VERSION 5.8 ;
BUSBITCHARS "[]" ;
DIVIDERCHAR "/" ;
UNITS
    DATABASE MICRONS 2000 ;
END UNITS

VIA softmax_rowwise_int8_r4_wrapper_via1_2_960_340_1_3_300_300
  VIARULE Via1Array-0 ;
  CUTSIZE 0.07 0.07 ;
  LAYERS metal1 via1 metal2 ;
  CUTSPACING 0.08 0.08 ;
  ENCLOSURE 0.035 0.05 0.035 0.035 ;
  ROWCOL 1 3 ;
END softmax_rowwise_int8_r4_wrapper_via1_2_960_340_1_3_300_300

VIA softmax_rowwise_int8_r4_wrapper_via2_3_960_340_1_3_320_320
  VIARULE Via2Array-0 ;
  CUTSIZE 0.07 0.07 ;
  LAYERS metal2 via2 metal3 ;
  CUTSPACING 0.09 0.09 ;
  ENCLOSURE 0.035 0.035 0.035 0.035 ;
  ROWCOL 1 3 ;
END softmax_rowwise_int8_r4_wrapper_via2_3_960_340_1_3_320_320

VIA softmax_rowwise_int8_r4_wrapper_via3_4_960_340_1_3_320_320
  VIARULE Via3Array-0 ;
  CUTSIZE 0.07 0.07 ;
  LAYERS metal3 via3 metal4 ;
  CUTSPACING 0.09 0.09 ;
  ENCLOSURE 0.035 0.035 0.045 0.035 ;
  ROWCOL 1 3 ;
END softmax_rowwise_int8_r4_wrapper_via3_4_960_340_1_3_320_320

VIA softmax_rowwise_int8_r4_wrapper_via4_5_960_2800_5_2_600_600
  VIARULE Via4Array-0 ;
  CUTSIZE 0.14 0.14 ;
  LAYERS metal4 via4 metal5 ;
  CUTSPACING 0.16 0.16 ;
  ENCLOSURE 0.02 0 0 0 ;
  ROWCOL 5 2 ;
END softmax_rowwise_int8_r4_wrapper_via4_5_960_2800_5_2_600_600

VIA softmax_rowwise_int8_r4_wrapper_via5_6_960_2800_5_2_600_600
  VIARULE Via5Array-0 ;
  CUTSIZE 0.14 0.14 ;
  LAYERS metal5 via5 metal6 ;
  CUTSPACING 0.16 0.16 ;
  ENCLOSURE 0 0 0 0 ;
  ROWCOL 5 2 ;
END softmax_rowwise_int8_r4_wrapper_via5_6_960_2800_5_2_600_600

VIA softmax_rowwise_int8_r4_wrapper_via6_7_960_2800_4_1_600_600
  VIARULE Via6Array-0 ;
  CUTSIZE 0.14 0.14 ;
  LAYERS metal6 via6 metal7 ;
  CUTSPACING 0.16 0.16 ;
  ENCLOSURE 0 0 0.13 0.18 ;
  ROWCOL 4 1 ;
END softmax_rowwise_int8_r4_wrapper_via6_7_960_2800_4_1_600_600

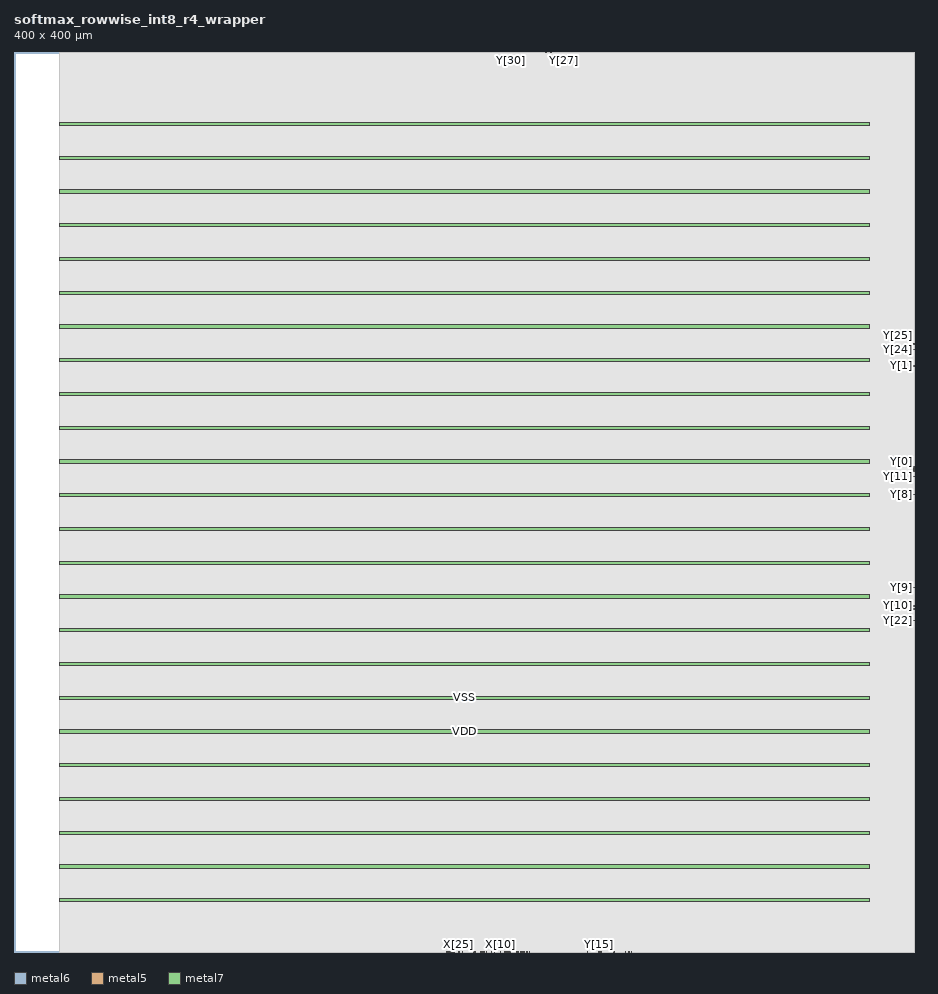
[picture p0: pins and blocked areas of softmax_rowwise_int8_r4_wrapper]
MACRO softmax_rowwise_int8_r4_wrapper
  FOREIGN softmax_rowwise_int8_r4_wrapper 0 0 ;
  CLASS BLOCK ;
  SIZE 400 BY 400 ;
  PIN X[0]
    DIRECTION INPUT ;
    USE SIGNAL ;
    PORT
      LAYER metal6 ;
        RECT  220.665 0 220.805 0.14 ;
    END
  END X[0]
  PIN X[10]
    DIRECTION INPUT ;
    USE SIGNAL ;
    PORT
      LAYER metal6 ;
        RECT  216.185 0 216.325 0.14 ;
    END
  END X[10]
  PIN X[11]
    DIRECTION INPUT ;
    USE SIGNAL ;
    PORT
      LAYER metal6 ;
        RECT  217.865 0 218.005 0.14 ;
    END
  END X[11]
  PIN X[12]
    DIRECTION INPUT ;
    USE SIGNAL ;
    PORT
      LAYER metal6 ;
        RECT  218.425 0 218.565 0.14 ;
    END
  END X[12]
  PIN X[13]
    DIRECTION INPUT ;
    USE SIGNAL ;
    PORT
      LAYER metal6 ;
        RECT  219.545 0 219.685 0.14 ;
    END
  END X[13]
  PIN X[14]
    DIRECTION INPUT ;
    USE SIGNAL ;
    PORT
      LAYER metal6 ;
        RECT  218.985 0 219.125 0.14 ;
    END
  END X[14]
  PIN X[15]
    DIRECTION INPUT ;
    USE SIGNAL ;
    PORT
      LAYER metal6 ;
        RECT  212.265 0 212.405 0.14 ;
    END
  END X[15]
  PIN X[16]
    DIRECTION INPUT ;
    USE SIGNAL ;
    PORT
      LAYER metal6 ;
        RECT  210.025 0 210.165 0.14 ;
    END
  END X[16]
  PIN X[17]
    DIRECTION INPUT ;
    USE SIGNAL ;
    PORT
      LAYER metal6 ;
        RECT  207.785 0 207.925 0.14 ;
    END
  END X[17]
  PIN X[18]
    DIRECTION INPUT ;
    USE SIGNAL ;
    PORT
      LAYER metal6 ;
        RECT  204.985 0 205.125 0.14 ;
    END
  END X[18]
  PIN X[19]
    DIRECTION INPUT ;
    USE SIGNAL ;
    PORT
      LAYER metal6 ;
        RECT  204.425 0 204.565 0.14 ;
    END
  END X[19]
  PIN X[1]
    DIRECTION INPUT ;
    USE SIGNAL ;
    PORT
      LAYER metal6 ;
        RECT  223.465 0 223.605 0.14 ;
    END
  END X[1]
  PIN X[20]
    DIRECTION INPUT ;
    USE SIGNAL ;
    PORT
      LAYER metal6 ;
        RECT  208.905 0 209.045 0.14 ;
    END
  END X[20]
  PIN X[21]
    DIRECTION INPUT ;
    USE SIGNAL ;
    PORT
      LAYER metal6 ;
        RECT  208.345 0 208.485 0.14 ;
    END
  END X[21]
  PIN X[22]
    DIRECTION INPUT ;
    USE SIGNAL ;
    PORT
      LAYER metal6 ;
        RECT  207.225 0 207.365 0.14 ;
    END
  END X[22]
  PIN X[23]
    DIRECTION INPUT ;
    USE SIGNAL ;
    PORT
      LAYER metal6 ;
        RECT  199.385 0 199.525 0.14 ;
    END
  END X[23]
  PIN X[24]
    DIRECTION INPUT ;
    USE SIGNAL ;
    PORT
      LAYER metal6 ;
        RECT  192.105 0 192.245 0.14 ;
    END
  END X[24]
  PIN X[25]
    DIRECTION INPUT ;
    USE SIGNAL ;
    PORT
      LAYER metal6 ;
        RECT  197.705 0 197.845 0.14 ;
    END
  END X[25]
  PIN X[26]
    DIRECTION INPUT ;
    USE SIGNAL ;
    PORT
      LAYER metal6 ;
        RECT  192.665 0 192.805 0.14 ;
    END
  END X[26]
  PIN X[27]
    DIRECTION INPUT ;
    USE SIGNAL ;
    PORT
      LAYER metal6 ;
        RECT  195.465 0 195.605 0.14 ;
    END
  END X[27]
  PIN X[28]
    DIRECTION INPUT ;
    USE SIGNAL ;
    PORT
      LAYER metal6 ;
        RECT  194.905 0 195.045 0.14 ;
    END
  END X[28]
  PIN X[29]
    DIRECTION INPUT ;
    USE SIGNAL ;
    PORT
      LAYER metal6 ;
        RECT  193.785 0 193.925 0.14 ;
    END
  END X[29]
  PIN X[2]
    DIRECTION INPUT ;
    USE SIGNAL ;
    PORT
      LAYER metal6 ;
        RECT  227.945 0 228.085 0.14 ;
    END
  END X[2]
  PIN X[30]
    DIRECTION INPUT ;
    USE SIGNAL ;
    PORT
      LAYER metal6 ;
        RECT  193.225 0 193.365 0.14 ;
    END
  END X[30]
  PIN X[31]
    DIRECTION INPUT ;
    USE SIGNAL ;
    PORT
      LAYER metal6 ;
        RECT  194.345 0 194.485 0.14 ;
    END
  END X[31]
  PIN X[3]
    DIRECTION INPUT ;
    USE SIGNAL ;
    PORT
      LAYER metal6 ;
        RECT  229.065 0 229.205 0.14 ;
    END
  END X[3]
  PIN X[4]
    DIRECTION INPUT ;
    USE SIGNAL ;
    PORT
      LAYER metal6 ;
        RECT  224.025 0 224.165 0.14 ;
    END
  END X[4]
  PIN X[5]
    DIRECTION INPUT ;
    USE SIGNAL ;
    PORT
      LAYER metal6 ;
        RECT  226.265 0 226.405 0.14 ;
    END
  END X[5]
  PIN X[6]
    DIRECTION INPUT ;
    USE SIGNAL ;
    PORT
      LAYER metal6 ;
        RECT  225.145 0 225.285 0.14 ;
    END
  END X[6]
  PIN X[7]
    DIRECTION INPUT ;
    USE SIGNAL ;
    PORT
      LAYER metal6 ;
        RECT  225.705 0 225.845 0.14 ;
    END
  END X[7]
  PIN X[8]
    DIRECTION INPUT ;
    USE SIGNAL ;
    PORT
      LAYER metal6 ;
        RECT  213.385 0 213.525 0.14 ;
    END
  END X[8]
  PIN X[9]
    DIRECTION INPUT ;
    USE SIGNAL ;
    PORT
      LAYER metal6 ;
        RECT  220.105 0 220.245 0.14 ;
    END
  END X[9]
  PIN Y[0]
    DIRECTION OUTPUT ;
    USE SIGNAL ;
    PORT
      LAYER metal5 ;
        RECT  399.86 214.48 400 214.62 ;
    END
  END Y[0]
  PIN Y[10]
    DIRECTION OUTPUT ;
    USE SIGNAL ;
    PORT
      LAYER metal5 ;
        RECT  399.86 154 400 154.14 ;
    END
  END Y[10]
  PIN Y[11]
    DIRECTION OUTPUT ;
    USE SIGNAL ;
    PORT
      LAYER metal5 ;
        RECT  399.86 211.12 400 211.26 ;
    END
  END Y[11]
  PIN Y[12]
    DIRECTION OUTPUT ;
    USE SIGNAL ;
    PORT
      LAYER metal5 ;
        RECT  399.86 213.92 400 214.06 ;
    END
  END Y[12]
  PIN Y[13]
    DIRECTION OUTPUT ;
    USE SIGNAL ;
    PORT
      LAYER metal5 ;
        RECT  399.86 213.36 400 213.5 ;
    END
  END Y[13]
  PIN Y[14]
    DIRECTION OUTPUT ;
    USE SIGNAL ;
    PORT
      LAYER metal6 ;
        RECT  236.345 399.86 236.485 400 ;
    END
  END Y[14]
  PIN Y[15]
    DIRECTION OUTPUT ;
    USE SIGNAL ;
    PORT
      LAYER metal6 ;
        RECT  259.865 0 260.005 0.14 ;
    END
  END Y[15]
  PIN Y[16]
    DIRECTION OUTPUT ;
    USE SIGNAL ;
    PORT
      LAYER metal5 ;
        RECT  399.86 152.32 400 152.46 ;
    END
  END Y[16]
  PIN Y[17]
    DIRECTION OUTPUT ;
    USE SIGNAL ;
    PORT
      LAYER metal6 ;
        RECT  260.425 0 260.565 0.14 ;
    END
  END Y[17]
  PIN Y[18]
    DIRECTION OUTPUT ;
    USE SIGNAL ;
    PORT
      LAYER metal6 ;
        RECT  274.425 0 274.565 0.14 ;
    END
  END Y[18]
  PIN Y[19]
    DIRECTION OUTPUT ;
    USE SIGNAL ;
    PORT
      LAYER metal6 ;
        RECT  271.625 0 271.765 0.14 ;
    END
  END Y[19]
  PIN Y[1]
    DIRECTION OUTPUT ;
    USE SIGNAL ;
    PORT
      LAYER metal5 ;
        RECT  399.86 260.4 400 260.54 ;
    END
  END Y[1]
  PIN Y[20]
    DIRECTION OUTPUT ;
    USE SIGNAL ;
    PORT
      LAYER metal6 ;
        RECT  254.825 0 254.965 0.14 ;
    END
  END Y[20]
  PIN Y[21]
    DIRECTION OUTPUT ;
    USE SIGNAL ;
    PORT
      LAYER metal5 ;
        RECT  399.86 153.44 400 153.58 ;
    END
  END Y[21]
  PIN Y[22]
    DIRECTION OUTPUT ;
    USE SIGNAL ;
    PORT
      LAYER metal5 ;
        RECT  399.86 147.28 400 147.42 ;
    END
  END Y[22]
  PIN Y[23]
    DIRECTION OUTPUT ;
    USE SIGNAL ;
    PORT
      LAYER metal6 ;
        RECT  273.305 0 273.445 0.14 ;
    END
  END Y[23]
  PIN Y[24]
    DIRECTION OUTPUT ;
    USE SIGNAL ;
    PORT
      LAYER metal5 ;
        RECT  399.86 267.68 400 267.82 ;
    END
  END Y[24]
  PIN Y[25]
    DIRECTION OUTPUT ;
    USE SIGNAL ;
    PORT
      LAYER metal5 ;
        RECT  399.86 270.48 400 270.62 ;
    END
  END Y[25]
  PIN Y[26]
    DIRECTION OUTPUT ;
    USE SIGNAL ;
    PORT
      LAYER metal5 ;
        RECT  399.86 269.92 400 270.06 ;
    END
  END Y[26]
  PIN Y[27]
    DIRECTION OUTPUT ;
    USE SIGNAL ;
    PORT
      LAYER metal6 ;
        RECT  244.185 399.86 244.325 400 ;
    END
  END Y[27]
  PIN Y[28]
    DIRECTION OUTPUT ;
    USE SIGNAL ;
    PORT
      LAYER metal6 ;
        RECT  243.625 399.86 243.765 400 ;
    END
  END Y[28]
  PIN Y[29]
    DIRECTION OUTPUT ;
    USE SIGNAL ;
    PORT
      LAYER metal6 ;
        RECT  239.145 399.86 239.285 400 ;
    END
  END Y[29]
  PIN Y[2]
    DIRECTION OUTPUT ;
    USE SIGNAL ;
    PORT
      LAYER metal5 ;
        RECT  399.86 215.04 400 215.18 ;
    END
  END Y[2]
  PIN Y[30]
    DIRECTION OUTPUT ;
    USE SIGNAL ;
    PORT
      LAYER metal6 ;
        RECT  220.665 399.86 220.805 400 ;
    END
  END Y[30]
  PIN Y[31]
    DIRECTION OUTPUT ;
    USE SIGNAL ;
    PORT
      LAYER metal6 ;
        RECT  266.585 0 266.725 0.14 ;
    END
  END Y[31]
  PIN Y[3]
    DIRECTION OUTPUT ;
    USE SIGNAL ;
    PORT
      LAYER metal5 ;
        RECT  399.86 215.6 400 215.74 ;
    END
  END Y[3]
  PIN Y[4]
    DIRECTION OUTPUT ;
    USE SIGNAL ;
    PORT
      LAYER metal6 ;
        RECT  242.505 399.86 242.645 400 ;
    END
  END Y[4]
  PIN Y[5]
    DIRECTION OUTPUT ;
    USE SIGNAL ;
    PORT
      LAYER metal6 ;
        RECT  238.585 399.86 238.725 400 ;
    END
  END Y[5]
  PIN Y[6]
    DIRECTION OUTPUT ;
    USE SIGNAL ;
    PORT
      LAYER metal6 ;
        RECT  220.105 399.86 220.245 400 ;
    END
  END Y[6]
  PIN Y[7]
    DIRECTION OUTPUT ;
    USE SIGNAL ;
    PORT
      LAYER metal6 ;
        RECT  260.985 0 261.125 0.14 ;
    END
  END Y[7]
  PIN Y[8]
    DIRECTION OUTPUT ;
    USE SIGNAL ;
    PORT
      LAYER metal5 ;
        RECT  399.86 203.28 400 203.42 ;
    END
  END Y[8]
  PIN Y[9]
    DIRECTION OUTPUT ;
    USE SIGNAL ;
    PORT
      LAYER metal5 ;
        RECT  399.86 161.84 400 161.98 ;
    END
  END Y[9]
  PIN clk
    DIRECTION INPUT ;
    USE SIGNAL ;
    PORT
      LAYER metal6 ;
        RECT  226.825 0 226.965 0.14 ;
    END
  END clk
  PIN VSS
    DIRECTION INOUT ;
    USE GROUND ;
    PORT
      LAYER metal7 ;
        RECT  20.14 352.3 380 353.7 ;
        RECT  20.14 322.3 380 323.7 ;
        RECT  20.14 292.3 380 293.7 ;
        RECT  20.14 262.3 380 263.7 ;
        RECT  20.14 232.3 380 233.7 ;
        RECT  20.14 202.3 380 203.7 ;
        RECT  20.14 172.3 380 173.7 ;
        RECT  20.14 142.3 380 143.7 ;
        RECT  20.14 112.3 380 113.7 ;
        RECT  20.14 82.3 380 83.7 ;
        RECT  20.14 52.3 380 53.7 ;
        RECT  20.14 22.3 380 23.7 ;
    END
  END VSS
  PIN VDD
    DIRECTION INOUT ;
    USE POWER ;
    PORT
      LAYER metal7 ;
        RECT  20.14 367.3 380 368.7 ;
        RECT  20.14 337.3 380 338.7 ;
        RECT  20.14 307.3 380 308.7 ;
        RECT  20.14 277.3 380 278.7 ;
        RECT  20.14 247.3 380 248.7 ;
        RECT  20.14 217.3 380 218.7 ;
        RECT  20.14 187.3 380 188.7 ;
        RECT  20.14 157.3 380 158.7 ;
        RECT  20.14 127.3 380 128.7 ;
        RECT  20.14 97.3 380 98.7 ;
        RECT  20.14 67.3 380 68.7 ;
        RECT  20.14 37.3 380 38.7 ;
    END
  END VDD
  OBS
    LAYER metal1 ;
     RECT  20.14 0 400 400 ;
    LAYER metal2 ;
     RECT  20.14 0 400 400 ;
    LAYER metal3 ;
     RECT  20.14 0 400 400 ;
    LAYER metal4 ;
     RECT  20.14 0 400 400 ;
    LAYER metal5 ;
     RECT  20.14 0 400 400 ;
    LAYER metal6 ;
     RECT  20.14 0 400 400 ;
    LAYER metal7 ;
     RECT  20.14 0 400 400 ;
    LAYER metal8 ;
     RECT  20.14 0 400 400 ;
    LAYER metal9 ;
     RECT  20.14 0 400 400 ;
  END
END softmax_rowwise_int8_r4_wrapper
END LIBRARY
